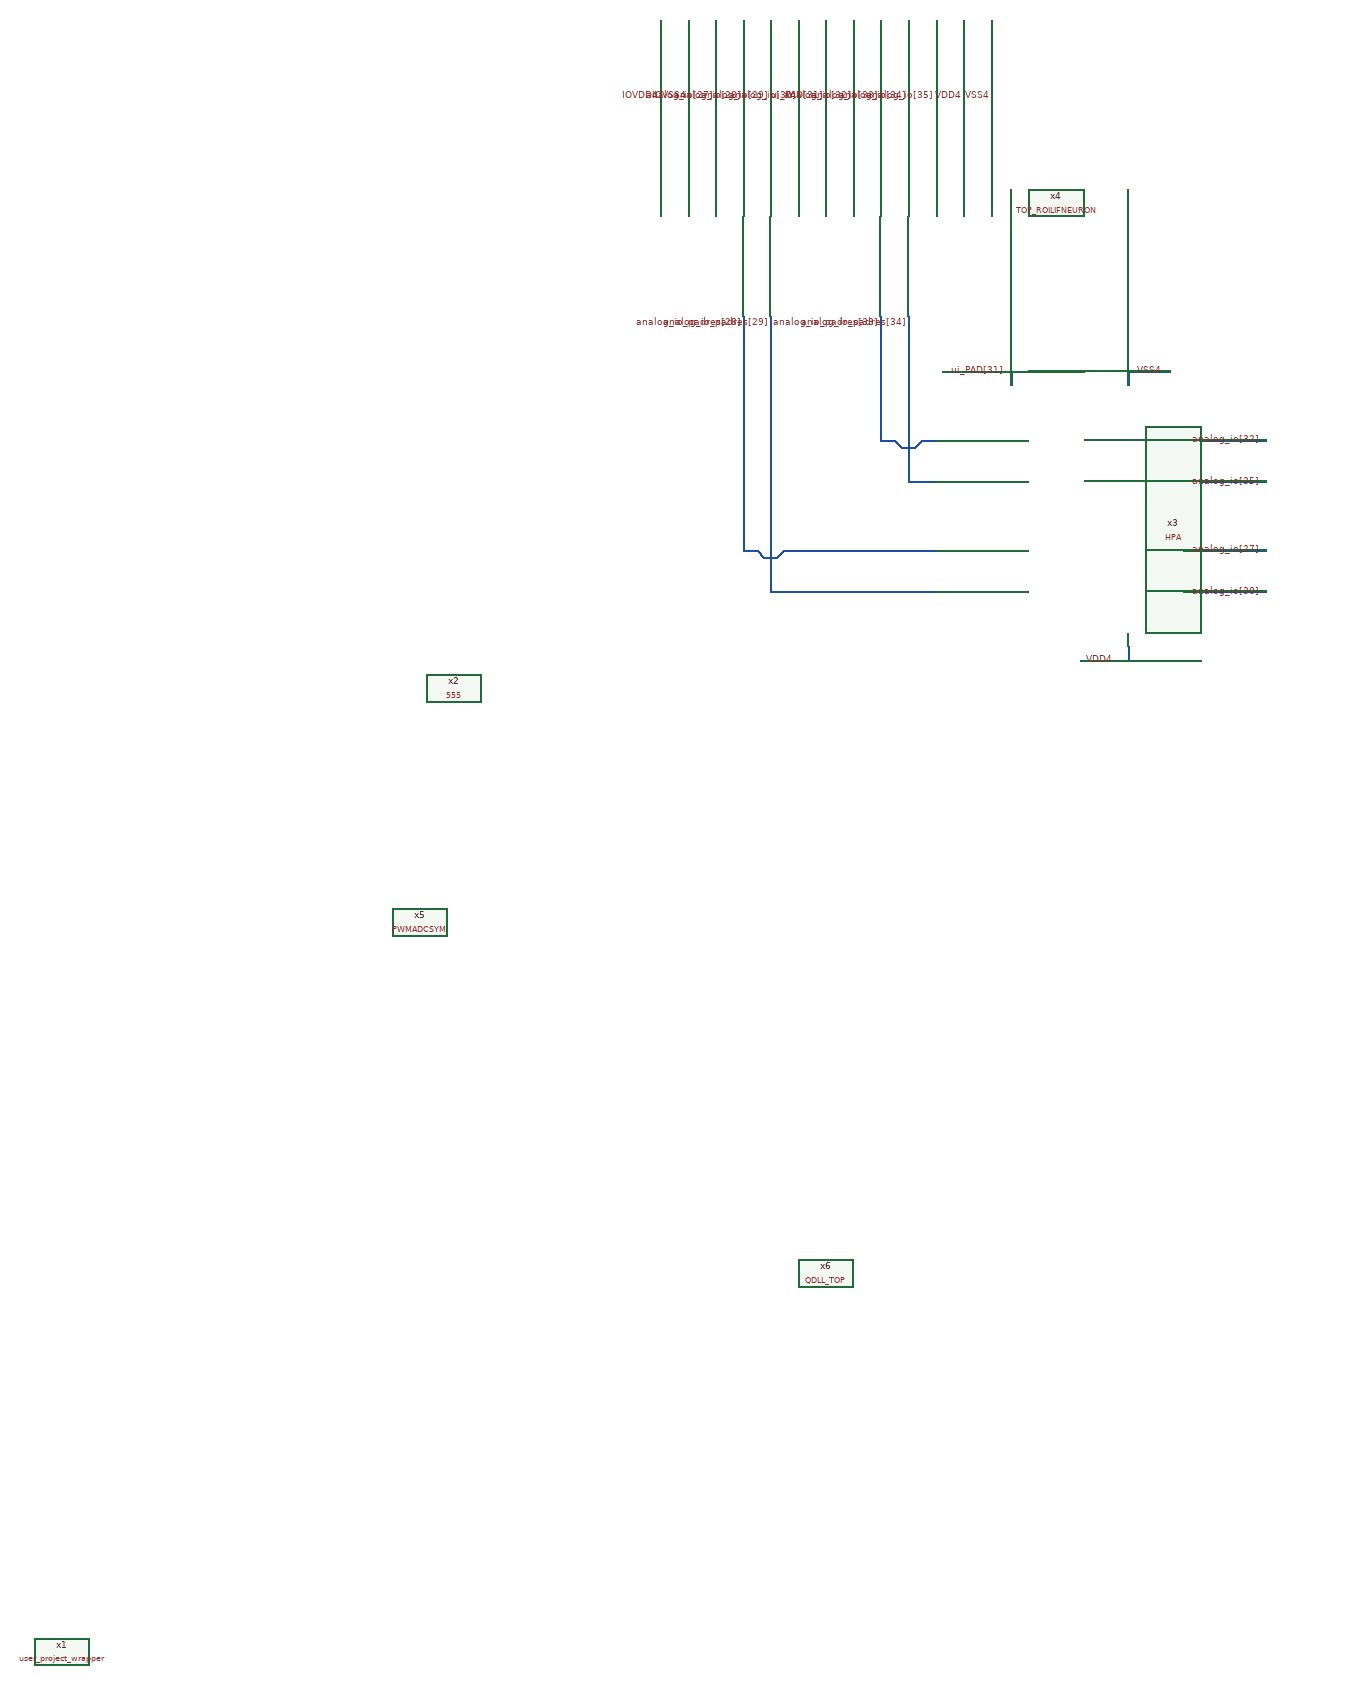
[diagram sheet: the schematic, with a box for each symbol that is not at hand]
v {xschem version=3.4.6 file_version=1.2}
G {}
K {}
V {}
S {}
E {}
N 1550 -1860 1610 -1860 {lab=VSS4}
N 1030 -2370 1030 -2240 {lab=analog_io[29]}
N 990 -2370 990 -2240 {lab=analog_io[28]}
N 1230 -2370 1230 -2240 {lab=analog_io[34]}
N 1190 -2370 1190 -2240 {lab=analog_io[33]}
N 1070 -2370 1070 -2240 {lab=analog_io[30]}
N 950 -2370 950 -2240 {lab=analog_io[27]}
N 1110 -2370 1110 -2240 {lab=ui_PAD[31]}
N 1150 -2370 1150 -2240 {lab=analog_io[32]}
N 1270 -2370 1270 -2240 {lab=analog_io[35]}
N 910 -2370 910 -2240 {lab=IOVSS4}
N 870 -2370 870 -2240 {lab=IOVDD4}
N 1350 -2370 1350 -2240 {lab=VSS4}
N 1310 -2370 1310 -2240 {lab=VDD4}
N 1630 -1700 1750 -1700 {lab=analog_io[35]}
N 1630 -1760 1750 -1760 {lab=analog_io[32]}
N 1630 -1600 1750 -1600 {lab=analog_io[27]}
N 1190 -1940 1190 -1760 {lab=analog_io_padres[33]}
N 1630 -1540 1750 -1540 {lab=analog_io[30]}
N 1190 -1760 1210 -1760 {lab=analog_io_padres[33]}
N 1210 -1760 1220 -1750 {lab=analog_io_padres[33]}
N 1220 -1750 1240 -1750 {lab=analog_io_padres[33]}
N 1240 -1750 1250 -1760 {lab=analog_io_padres[33]}
N 990 -1600 1010 -1600 {lab=analog_io_padres[28]}
N 990 -1940 990 -1600 {lab=analog_io_padres[28]}
N 1010 -1600 1020 -1590 {lab=analog_io_padres[28]}
N 1020 -1590 1040 -1590 {lab=analog_io_padres[28]}
N 1040 -1590 1050 -1600 {lab=analog_io_padres[28]}
N 1380 -1860 1380 -1840 {lab=ui_PAD[31]}
N 1280 -1860 1380 -1860 {lab=ui_PAD[31]}
N 1550 -1860 1550 -1840 {lab=VSS4}
N 1550 -1460 1550 -1440 {lab=VDD4}
N 1480 -1440 1550 -1440 {lab=VDD4}
N 1250 -1760 1270 -1760 {lab=analog_io_padres[33]}
N 1230 -1700 1270 -1700 {lab=analog_io_padres[34]}
N 1050 -1600 1270 -1600 {lab=analog_io_padres[28]}
N 1030 -1540 1270 -1540 {lab=analog_io_padres[29]}
N 1230 -1940 1230 -1700 {lab=analog_io_padres[34]}
N 1030 -1940 1030 -1540 {lab=analog_io_padres[29]}
C {IHP__MPC0349/MPC0349-main/schematic/xschem/user_project_wrapper.sym} 0 0 0 0 {name=x1}
C {IHP__MPC0349/dependencies/IHP__OSC3593/OSC3593-main/schematic/xschem/555.sym} 570 -1400 0 0 {name=x2}
C {IHP__MPC0349/dependencies/IHP__OPA2251/OPA2251-main/schematic/xschem/HPA.sym} 1720 -1270 0 0 {name=x3}
C {IHP__MPC0349/dependencies/IHP__OSC9996/OSC9996-main/schematic/xschem/TOP_ROILIFNEURON.sym} 1250 -1860 2 1 {name=x4}
C {IHP__MPC0349/dependencies/IHP__QDLL6501/QDLL6501-main/schematic/xschem/QDLL_TOP.sym} 1110 -550 0 0 {name=x6}
C {IHP__MPC0349/dependencies/IHP__OSC3593/OSC3593-main/schematic/xschem/PWMADCSYM.sym} 520 -1060 0 0 {name=x5}
C {lab_wire.sym} 1640 -1540 2 0 {name=p4 sig_type=std_logic lab=analog_io[30]	}
C {lab_wire.sym} 1640 -1600 2 0 {name=p5 sig_type=std_logic lab=analog_io[27]	}
C {lab_wire.sym} 1640 -1700 2 0 {name=p6 sig_type=std_logic lab=analog_io[35]	}
C {lab_wire.sym} 1640 -1760 2 0 {name=p7 sig_type=std_logic lab=analog_io[32]	}
C {lab_wire.sym} 1530 -1440 0 0 {name=p8 sig_type=std_logic lab=VDD4	}
C {lab_wire.sym} 1560 -1860 0 1 {name=p10 sig_type=std_logic lab=VSS4	}
C {lab_wire.sym} 1290 -1860 0 1 {name=p11 sig_type=std_logic lab=ui_PAD[31]	}
C {lab_wire.sym} 1030 -2260 1 0 {name=p12 sig_type=std_logic lab=analog_io[29]	}
C {lab_wire.sym} 990 -2260 1 0 {name=p13 sig_type=std_logic lab=analog_io[28]	}
C {lab_wire.sym} 1230 -2260 1 0 {name=p14 sig_type=std_logic lab=analog_io[34]	}
C {lab_wire.sym} 1190 -2260 1 0 {name=p15 sig_type=std_logic lab=analog_io[33]	}
C {lab_wire.sym} 1070 -2260 1 0 {name=p16 sig_type=std_logic lab=analog_io[30]	}
C {lab_wire.sym} 950 -2260 1 0 {name=p17 sig_type=std_logic lab=analog_io[27]	}
C {lab_wire.sym} 1110 -2260 1 0 {name=p18 sig_type=std_logic lab=ui_PAD[31]	}
C {lab_wire.sym} 1150 -2260 1 0 {name=p19 sig_type=std_logic lab=analog_io[32]	}
C {lab_wire.sym} 1270 -2260 1 0 {name=p20 sig_type=std_logic lab=analog_io[35]	}
C {lab_wire.sym} 910 -2260 1 0 {name=p21 sig_type=std_logic lab=IOVSS4	}
C {lab_wire.sym} 870 -2260 1 0 {name=p22 sig_type=std_logic lab=IOVDD4	}
C {lab_wire.sym} 1350 -2260 1 0 {name=p23 sig_type=std_logic lab=VSS4}
C {lab_wire.sym} 1310 -2260 1 0 {name=p24 sig_type=std_logic lab=VDD4	}
C {lab_wire.sym} 990 -1930 3 0 {name=p26 sig_type=std_logic lab=analog_io_padres[28]	}
C {lab_wire.sym} 1030 -1930 3 0 {name=p1 sig_type=std_logic lab=analog_io_padres[29]	}
C {lab_wire.sym} 1230 -1930 1 1 {name=p29 sig_type=std_logic lab=analog_io_padres[34]	}
C {lab_wire.sym} 1190 -1930 1 1 {name=p27 sig_type=std_logic lab=analog_io_padres[33]	}
